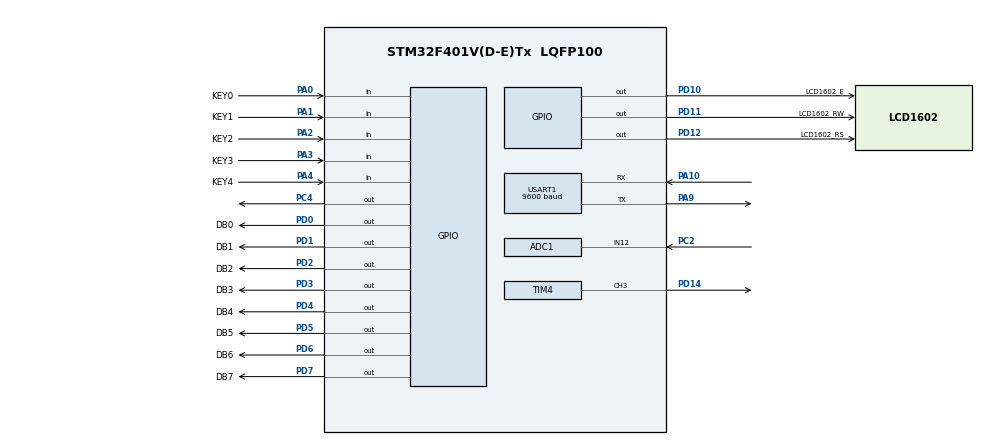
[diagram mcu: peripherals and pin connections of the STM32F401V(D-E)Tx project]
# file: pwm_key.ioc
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ADC1.Channel-3\#ChannelRegularConversion=ADC_CHANNEL_12
ADC1.ClockPrescaler=ADC_CLOCK_SYNC_PCLK_DIV4
ADC1.ContinuousConvMode=ENABLE
ADC1.NbrOfConversionFlag=1
ADC1.Rank-3\#ChannelRegularConversion=1
ADC1.SamplingTime-3\#ChannelRegularConversion=ADC_SAMPLETIME_3CYCLES
ADC1.master=1
Mcu.Family=STM32F4
Mcu.Name=STM32F401V(D-E)Tx
Mcu.Package=LQFP100
NVIC.PriorityGroup=NVIC_PRIORITYGROUP_4
PA0-WKUP.GPIO_Label=KEY0
PA0-WKUP.GPIO_Mode=GPIO_MODE_INPUT
PA0-WKUP.GPIO_PuPd=GPIO_NOPULL
PA0-WKUP.Signal=GPIO_Input
PA1.GPIO_Label=KEY1
PA1.GPIO_Mode=GPIO_MODE_INPUT
PA1.GPIO_PuPd=GPIO_NOPULL
PA1.Signal=GPIO_Input
PA10.Mode=Asynchronous
PA10.Signal=USART1_RX
PA13.Mode=Serial_Wire
PA13.Signal=SYS_JTMS-SWDIO
PA14.Mode=Serial_Wire
PA14.Signal=SYS_JTCK-SWCLK
PA2.GPIO_Label=KEY2
PA2.GPIO_Mode=GPIO_MODE_INPUT
PA2.GPIO_PuPd=GPIO_NOPULL
PA2.Signal=GPIO_Input
PA3.GPIO_Label=KEY3
PA3.GPIO_Mode=GPIO_MODE_INPUT
PA3.GPIO_PuPd=GPIO_NOPULL
PA3.Signal=GPIO_Input
PA4.GPIO_Label=KEY4
PA4.GPIO_Mode=GPIO_MODE_INPUT
PA4.GPIO_PuPd=GPIO_NOPULL
PA4.Signal=GPIO_Input
PA9.Mode=Asynchronous
PA9.Signal=USART1_TX
PC14-OSC32_IN.Mode=LSE-External-Oscillator
PC14-OSC32_IN.Signal=RCC_OSC32_IN
PC15-OSC32_OUT.Mode=LSE-External-Oscillator
PC15-OSC32_OUT.Signal=RCC_OSC32_OUT
PC2.Signal=ADCx_IN12
PC4.PinState=GPIO_PIN_SET
PC4.Signal=GPIO_Output
PD0.GPIO_Label=DB0
PD0.Signal=GPIO_Output
PD1.GPIO_Label=DB1
PD1.Signal=GPIO_Output
PD10.GPIO_Label=LCD1602_E
PD10.Signal=GPIO_Output
PD11.GPIO_Label=LCD1602_RW
PD11.Signal=GPIO_Output
PD12.GPIO_Label=LCD1602_RS
PD12.Signal=GPIO_Output
PD14.Signal=S_TIM4_CH3
PD2.GPIO_Label=DB2
PD2.Signal=GPIO_Output
PD3.GPIO_Label=DB3
PD3.Signal=GPIO_Output
PD4.GPIO_Label=DB4
PD4.Signal=GPIO_Output
PD5.GPIO_Label=DB5
PD5.Signal=GPIO_Output
PD6.GPIO_Label=DB6
PD6.Signal=GPIO_Output
PD7.GPIO_Label=DB7
PD7.Signal=GPIO_Output
PH0\ -\ OSC_IN.Mode=HSE-External-Oscillator
PH0\ -\ OSC_IN.Signal=RCC_OSC_IN
PH1\ -\ OSC_OUT.Mode=HSE-External-Oscillator
PH1\ -\ OSC_OUT.Signal=RCC_OSC_OUT
ProjectManager.HeapSize=0x200
ProjectManager.StackSize=0x400
ProjectManager.TargetToolchain=MDK-ARM V5.27
RCC.48MHZClocksFreq_Value=42000000
RCC.AHBFreq_Value=84000000
RCC.APB1CLKDivider=RCC_HCLK_DIV2
RCC.APB1Freq_Value=42000000
RCC.APB1TimFreq_Value=84000000
RCC.APB2Freq_Value=84000000
RCC.APB2TimFreq_Value=84000000
RCC.CortexFreq_Value=84000000
RCC.HCLKFreq_Value=84000000
RCC.HSE_VALUE=8000000
RCC.HSI_VALUE=16000000
RCC.PLLN=168
RCC.SYSCLKFreq_VALUE=84000000
RCC.SYSCLKSource=RCC_SYSCLKSOURCE_PLLCLK
RCC.VCOOutputFreq_Value=168000000
SH.ADCx_IN12.0=ADC1_IN12,IN12
SH.S_TIM4_CH3.0=TIM4_CH3,PWM Generation3 CH3
TIM4.AutoReloadPreload=TIM_AUTORELOAD_PRELOAD_ENABLE
TIM4.Channel-PWM\ Generation3\ CH3=TIM_CHANNEL_3
TIM4.Period=99
TIM4.Prescaler=83
USART1.BaudRate=9600
USART1.VirtualMode=VM_ASYNC
VP_TIM4_VS_ClockSourceINT.Mode=Internal
board=custom

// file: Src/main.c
/* USER CODE BEGIN Header */
/**
  ******************************************************************************
  * @file           : main.c
  * @brief          : Main program body
  ******************************************************************************
  * @attention
  *
  * <h2><center>&copy; Copyright (c) 2020 STMicroelectronics.
  * All rights reserved.</center></h2>
  *
  * This software component is licensed by ST under BSD 3-Clause license,
  * the "License"; You may not use this file except in compliance with the
  * License. You may obtain a copy of the License at:
  *                        opensource.org/licenses/BSD-3-Clause
  *
  ******************************************************************************
  */
/* USER CODE END Header */

#include "main.h"
#include "adc.h"
#include "tim.h"
#include "usart.h"
#include "gpio.h"

/* USER CODE BEGIN Includes */
#include "stdio.h"

uint16_t pwm_value = 0;
uint8_t flag=0;
uint8_t humi=35;
uint8_t temp=25;
uint8_t mode1=0;
uint8_t menu=0;
uint8_t key_num=0;
uint16_t num1=0;
uint16_t num2=0;
uint16_t pwmt=0;
uint16_t pwmh=0;
/* USER CODE END Includes */

/* USER CODE BEGIN PTD */

void write_guanbiao(uint8_t x,uint8_t y,uint8_t date)
{
	if(y==0)
	LCD1602_WriteCmd(0x80+x);
	else
	LCD1602_WriteCmd(0x80+0x40+x);
	if(date == 1)
	LCD1602_WriteCmd(0x0f); //�����˸
	else
	LCD1602_WriteCmd(0x0c); //�رչ��
}

uint8_t MAX(uint8_t x,uint8_t y)
{
	uint8_t max;
	if(x>y) max=x;
	else max=y;
	return max;
}

//void key_with(void)
//{
//	key_num=keyscan(0);
//	if(key_num==1)
//	{
//		mode1++;
//		LCD1602_WriteCmd(0x01);
//		if(mode1>1)
//		{
//			mode1 = 0;
//			menu = 0;
//			LCD1602_WriteCmd(0x0c);
//		}
//		key_num=0;
//	}
//	if(mode1==0)
//	{
//		LCD1602_ShowStr(0,0,"H   T   FAN    ",15);
//		LCD1602_ShowChar(0,1,(uint8_t)humidity/10+0x30);
//		LCD1602_ShowChar(1,1,(uint8_t)humidity%10+0x30);
//		LCD1602_ShowChar(4,1,(uint8_t)temperature/10+0x30);
//		LCD1602_ShowChar(5,1,(uint8_t)temperature%10+0x30);
//		if(pwm_value==0)	LCD1602_ShowStr(8,1,"OFF",3);
//		else							LCD1602_ShowStr(8,1,"ON ",3);
//	}
//	if(key_num==5)
//	{
//		mode1 = 0;
//		menu = 0;
//		LCD1602_WriteCmd(0x01);
//		LCD1602_WriteCmd(0x0c);
//		key_num=0;
//	}
//	if(mode1==1)
//	{
//		LCD1602_ShowStr(0,0,"SET   H   T",11);
//		LCD1602_ShowChar(6,1, humi/10+0x30);
//		LCD1602_ShowChar(7,1, humi%10+0x30);
//		LCD1602_ShowChar(10,1,temp/10+0x30);
//		LCD1602_ShowChar(11,1,temp%10+0x30);
//		if(menu==0)
//		{
//			if(key_num==3)
//			{
//				humi++;
//				key_num=0;
//			}
//			if(key_num==4)
//			{
//				humi--;
//				key_num=0;
//			}
//			if(key_num==2)
//			{
//				menu++;
//				if(menu>1) menu = 0;
//			}
//			LCD1602_ShowChar(6,1, humi/10+0x30);
//			LCD1602_ShowChar(7,1, humi%10+0x30);
//			write_guanbiao(6,0,1);
//		}
//		if(menu==1)
//		{
//			if(key_num==3)
//			{
//				temp++;
//				key_num=0;
//			}
//			if(key_num==4)
//			{
//				temp--;
//				key_num=0;
//			}
//			if(key_num==2)
//			{
//				menu++;
//				if(menu>1) menu = 0;
//			}
//			LCD1602_ShowChar(10,1,temp/10+0x30);
//			LCD1602_ShowChar(11,1,temp%10+0x30);
//			write_guanbiao(10,0,1);
//		}
//	}
//}

void key_system(void)
{
	key_num=keyscan(0);
	switch(key_num)
	{
		case 1:
			mode1++;
			flag=1;
			LCD1602_WriteCmd(0x01);
			if(mode1>1)
			{
				mode1 = 0;
				menu = 0;
				LCD1602_WriteCmd(0x0c);
			}
			break;
		case 2:
			if(mode1==0) break;
			else
			{
				flag=1;
				menu++;
				if(menu>1)
				{
					menu = 0;
				}
			}
			break;
		case 3:
			if(mode1==0) break;
			flag=1;
			if(menu==0) humi++;
			else				temp++;
			break;
		case 4:
			if(mode1==0) break;
			flag=1;
			if(menu==0) humi--;
			else				temp--;
			break;
		case 5:
			if(mode1==0) break;
			else
			{
				mode1 = 0;
				menu = 0;
				LCD1602_WriteCmd(0x01);
				LCD1602_WriteCmd(0x0c);
			}
			break;
		default: break;
	}
}

uint16_t FAN_control(void)
{
	uint16_t pwm;
	if(temperature<temp && humidity<humi)	 pwm=0;
	if(temperature>36 && temperature>temp) pwm=100;
	if(humidity>80 && humidity>humi)       pwm=100;
	if(temperature>=temp || humidity>=humi)
	{
		if(humidity<=80 && humidity>=humi)
		{
			num1=(uint8_t)humidity-humi;
			num2=80-humi;
			pwmh=num1*100/num2;
		}
		if(temperature<=36 && temperature>=temp)
		{
			num1=(uint8_t)temperature-temp;
			num2=36-temp;
			pwmh=num1*100/num2;
		}
		pwm=MAX(pwmh,pwmt);
	}
	if(temperature>36 && temperature>temp) pwm=100;
	if(humidity>80 && humidity>humi)       pwm=100;
	return pwm;
}
/* USER CODE END PTD */

/* USER CODE BEGIN PFP */
void SystemClock_Config_FW(void);
void SystemClock_Config(void);
/* USER CODE END PFP */

int main(void)
{
  /* USER CODE BEGIN 1 */
  HAL_Init();
  SystemClock_Config_FW();
	SystemClock_Config();
  MX_GPIO_Init();
	LCD1602_Init();
	LCD1602_ShowStr(0,0,"INT...",6);
  MX_TIM4_Init();
  MX_ADC1_Init();
  MX_USART1_UART_Init();
	HAL_TIM_PWM_Start(&htim4,TIM_CHANNEL_3);
  HAL_Delay(100);
  /* USER CODE END 1 */
  while (1)
  {
    /* USER CODE BEGIN 3 */
//		key_with();
		DHT11_Show_Data();
		get_ADValue();
		do
		{
			key_system();
			if(mode1==0)
			{
				LCD1602_ShowStr(0,0,"H   T   FAN    ",15);
				LCD1602_ShowChar(0,1,(uint8_t)humidity/10+0x30);
				LCD1602_ShowChar(1,1,(uint8_t)humidity%10+0x30);
				LCD1602_ShowChar(4,1,(uint8_t)temperature/10+0x30);
				LCD1602_ShowChar(5,1,(uint8_t)temperature%10+0x30);
				if(pwm_value==0)	LCD1602_ShowStr(8,1,"OFF",3);
				else							LCD1602_ShowStr(8,1,"ON ",3);
			}
			else
			{
				if(menu==0&&flag==1)
				{
					LCD1602_ShowStr(0,0,"SET   H   T",11);
					LCD1602_ShowChar(6,1, humi/10+0x30);
					LCD1602_ShowChar(7,1, humi%10+0x30);
					LCD1602_ShowChar(10,1,temp/10+0x30);
					LCD1602_ShowChar(11,1,temp%10+0x30);
					write_guanbiao(6,0,1);
					flag=0;
					HAL_Delay(200);
				}
				else if(flag==1)
				{
					LCD1602_ShowStr(0,0,"SET   H   T",11);
					LCD1602_ShowChar(6,1, humi/10+0x30);
					LCD1602_ShowChar(7,1, humi%10+0x30);
					LCD1602_ShowChar(10,1,temp/10+0x30);
					LCD1602_ShowChar(11,1,temp%10+0x30);
					write_guanbiao(10,0,1);
					flag=0;
					HAL_Delay(200);
				}
			}
		}while(mode1==1);
		pwm_value=FAN_control();
		__HAL_TIM_SET_COMPARE(&htim4,TIM_CHANNEL_3,pwm_value);
		HAL_Delay(10);
  }
  /* USER CODE END 3 */
}

void SystemClock_Config(void)
{
  RCC_OscInitTypeDef RCC_OscInitStruct = {0};
  RCC_ClkInitTypeDef RCC_ClkInitStruct = {0};

  __HAL_RCC_PWR_CLK_ENABLE();
  __HAL_PWR_VOLTAGESCALING_CONFIG(PWR_REGULATOR_VOLTAGE_SCALE2);

  RCC_OscInitStruct.OscillatorType = RCC_OSCILLATORTYPE_HSI;
  RCC_OscInitStruct.HSIState = RCC_HSI_ON;
  RCC_OscInitStruct.HSICalibrationValue = RCC_HSICALIBRATION_DEFAULT;
  RCC_OscInitStruct.PLL.PLLState = RCC_PLL_NONE;
  if (HAL_RCC_OscConfig(&RCC_OscInitStruct) != HAL_OK)
  {
    Error_Handler();
  }

  RCC_ClkInitStruct.ClockType = RCC_CLOCKTYPE_HCLK|RCC_CLOCKTYPE_SYSCLK
                              |RCC_CLOCKTYPE_PCLK1|RCC_CLOCKTYPE_PCLK2;
  RCC_ClkInitStruct.SYSCLKSource = RCC_SYSCLKSOURCE_HSI;
  RCC_ClkInitStruct.AHBCLKDivider = RCC_SYSCLK_DIV1;
  RCC_ClkInitStruct.APB1CLKDivider = RCC_HCLK_DIV1;
  RCC_ClkInitStruct.APB2CLKDivider = RCC_HCLK_DIV1;
  if (HAL_RCC_ClockConfig(&RCC_ClkInitStruct, FLASH_LATENCY_0) != HAL_OK)
  {
    Error_Handler();
  }

}

void SystemClock_Config_FW(void)
{
  RCC_OscInitTypeDef RCC_OscInitStruct = {0};
  RCC_ClkInitTypeDef RCC_ClkInitStruct = {0};

  /** Configure the main internal regulator output voltage
  */
  __HAL_RCC_PWR_CLK_ENABLE();
  __HAL_PWR_VOLTAGESCALING_CONFIG(PWR_REGULATOR_VOLTAGE_SCALE2);
  /** Initializes the CPU, AHB and APB busses clocks
  */
  RCC_OscInitStruct.OscillatorType = RCC_OSCILLATORTYPE_HSE;
  RCC_OscInitStruct.HSIState = RCC_HSE_ON;
//  RCC_OscInitStruct.HSICalibrationValue = RCC_HSICALIBRATION_DEFAULT;
  RCC_OscInitStruct.PLL.PLLState = RCC_PLL_ON;
  RCC_OscInitStruct.PLL.PLLSource = RCC_PLLSOURCE_HSE;
  RCC_OscInitStruct.PLL.PLLM = 6;
  RCC_OscInitStruct.PLL.PLLN = 168;
  RCC_OscInitStruct.PLL.PLLP = RCC_PLLP_DIV4;
  RCC_OscInitStruct.PLL.PLLQ = 4;
  if (HAL_RCC_OscConfig(&RCC_OscInitStruct) != HAL_OK)
  {
    Error_Handler();
  }
  /** Initializes the CPU, AHB and APB busses clocks
  */
  RCC_ClkInitStruct.ClockType = RCC_CLOCKTYPE_HCLK|RCC_CLOCKTYPE_SYSCLK
                              |RCC_CLOCKTYPE_PCLK1|RCC_CLOCKTYPE_PCLK2;
  RCC_ClkInitStruct.SYSCLKSource = RCC_SYSCLKSOURCE_PLLCLK;
  RCC_ClkInitStruct.AHBCLKDivider = RCC_SYSCLK_DIV1;
  RCC_ClkInitStruct.APB1CLKDivider = RCC_HCLK_DIV2;
  RCC_ClkInitStruct.APB2CLKDivider = RCC_HCLK_DIV1;

  if (HAL_RCC_ClockConfig(&RCC_ClkInitStruct, FLASH_LATENCY_2) != HAL_OK)
  {
    Error_Handler();
  }
}

void Error_Handler(void)
{
}

/************************ (C) COPYRIGHT STMicroelectronics *****END OF FILE****/
